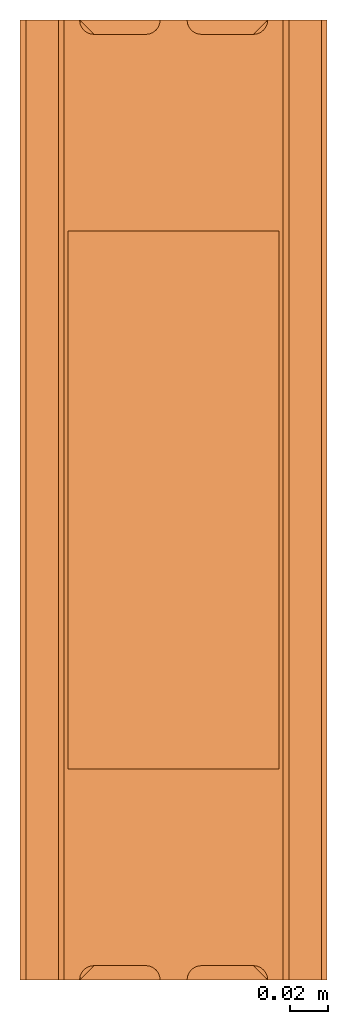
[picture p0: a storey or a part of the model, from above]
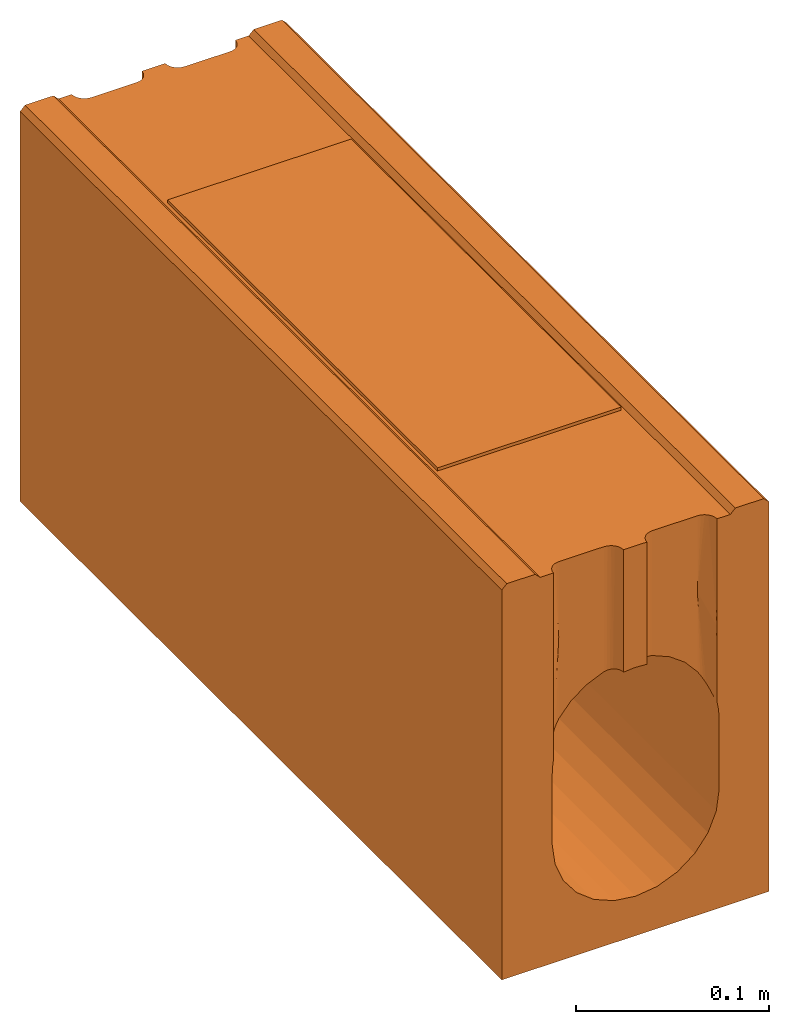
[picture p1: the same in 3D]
Properties of the parts of a building model (IFC2X3)

# File
Description: ViewDefinition [CoordinationView]
File name: 32103 - PD100 F 10.3 Rodding Access 500mm LG.ifc
Time: 2013-10-11T12:30:02
Written by: Autodesk Revit 2013
Made in: 20120221_2030(x64)

# IfcProject, Project Number
LongName: Project Name; Phase: Project Status

# IfcSite, Default
RefLatitude: 42, 21, 30, 344238; RefLongitude: -71, -3, -35, -194702; RefElevation: 0 mm

# IfcBuilding
Pset_BuildingCommon - NumberOfStoreys: 2
Other - Project Status: Project Status; Project Issue Date: Issue Date; Client Name: Owner; Project Address: Enter address here; Project Number: Project Number; Project Name: Project Name

# IfcBuildingStorey (2)
Constraints - Elevation Base: 0
Graphics - Symbol: M_Level Head - Circle: M_Level Head - Circle; Line Weight: 1; Line Pattern: Center; Symbol at End 2 Default: yes; Symbol at End 1 Default: no; Color: 0
Identity Data - Building Story: yes; Structural: no
Dimensions - Computation Height: 0 mm
Name | LongName = Name | Elevation (mm) = Constraints, Elevation (mm)
B.O. Footing | B.O. Footing | -4600
T.O. Footing | T.O. Footing | -4300

# IfcBuildingElementProxy: 32103 - PD100 F 10.3 Rodding Access 500mm LG, Civil-Drainage-Channel-ACO-RoadDrain 100:32103 - PD100 F 10.3 Rodding Access 500mm LG:32103 - PD100 F 10.3 Rodding Access 500mm LG:310733
In: B.O. Footing
Material: Acetal Resin, Black
Other - Revision: 1; CreatedBy: www.aco.co.uk
Green Building Properties - End Cap Recyclable: N/A; Access Cover/Frame Recycled Material Content: Between 40% - 90%; Grating Recycled Material Content: N/A; End Cap Recycled Material Content: N/A; Channel Recycled Material Content: 20% minimum; Grating Recyclable: N/A; Access Cover/Frame Recyclable: Fully recyclable; Channel Recyclable: Fully recyclable
Construction - 32900 - Sump Unit: no; Inlet Outlet end cap_350 high: no; Closing End Cap: no; Access unit: yes; Inlet Outlet end cap_450 high: no; Channel 160mm Wide: no; Grating 500mm: no
Dimensions - Straight Void Length: 500 mm; Volume: 13568465 mm3; Length: 500 mm; Custom Void Length: 0 mm; I/O End Cap Void: 3000 mm; Void Depth: -250 mm; Total Depth: 250 mm; Straight Void Start: 0 mm; Invert Depth.: 175 mm
Phasing - Phase Created: Phase 1
Constraints - Moves With Nearby Elements: no; Level: Level: T.O. Footing
Pset_BuildingElementProxyCommon - Reference: 32103 - PD100 F 10.3 Rodding Access 500mm LG
Identity Data - Product Page URL: http://www.aco.co.uk/product_detail.php?id=21; Address: ACO Business Park, Hitchin Road, Shefford, Bedfordshire, United Kingdom SG17 5TE; Assembly Description: Rain Water Drainage; Cost: 0; Type Comments: ACO RoadDrain 100 PD100F 10.3 Constant Depth Access Channel 500mm Long; Model: ACO RoadDrain 100 PD100F; Price: POA - contact ACO; Installation guidelines: http://www.aco.co.uk/download.php?id=256; URL: www.aco.co.uk; Manufacturer: ACO Technologies plc - ACO Water Management Division; Watermarked By: www.aco.co.uk; Watermark 1: This file is the property of ACO Technologies PLC; Telephone: +44 (0)1462 816666; e-mail Technical: technical@aco.co.uk; Assembly Code: D2040; OmniClass Title: Rainwater Removal; Product Code: 32103; Watermarked With: BIM Manager Premium Suite; OmniClass Number: 23.70.50.24; Watermark 2: This file is water marked and users are prohibited to reproduce, adapt, distribute this information; Product brochure: http://www.aco.co.uk/download.php?id=256; Fax: +44 (0)1462 815895; Maintenance guidelines: http://www.aco.co.uk/download.php?id=256; e-mail Sales: customersupport@aco.co.uk; Model Description: Monolithic Channel drainage system
Materials and Finishes - Access Cover/Frame Material: Ductile Iron; End Cap Colour: N/A; Access Cover/Frame Finish: Water Based Paint Coating; Access Cover/Frame Colour: Black; Channel Colour: Black; End Cap Material: N/A; Connection Pipe Colour: N/A; Channel Material: Vienite® Synthetic Resin Concrete; Grating Finish: N/A; Grating Colour: N/A; Connection Pipe Material: N/A; Grating Material: N/A
Data - Product Dimensions: 500mm x 160mm x 250mm (LxWxH); Product Standard: BE EN1433:2002, CE Marked, Kitemarked; ACO Hydraulic Design Software: http://www.acodesign.co.uk; Product Weight: 26.4 Kg; Load Class: A 15 - F 900; Hydraulic Performance: http://www.aco.co.uk/download.php?id=256; Connection Pipe O.D: N/A; Invert Depth: 225mm; Concrete Surround Volume - Load Class F 900 - Concrete Pavement: 0.22m³; Installation - Concrete Grade: Refer to brochure; Channel C.S.A: 0.012m²
General - TagNumber: 0.000000; SerialNumber: 0.000000

# IfcOpeningElement: Recess (2)
In: T.O. Footing
Constraints - Level: Level: T.O. Footing; Height Offset From Level: 0 mm; Room Bounding: yes; Related to Mass: no
Dimensions - Perimeter: 22200 mm; Thickness: 1550 mm; Volume: 47720000000 mm3; Area: 30800000 mm2
Structural - Structural: no; Enable Analytical Model: no
Phasing - Phase Created: Phase 1
Analytical Properties - Thermal Resistance (R): 1.79211; Roughness: 1; Heat Transfer Coefficient (U): 0.558; Thermal mass: 2039700; Absorptance: 0.1
Construction - Default Thickness: 1550 mm; Function: 0
Materials and Finishes - Structural Material: Grass
Graphics - Coarse Scale Fill Color: 0

# IfcSlab: Floor:Generic Floor - 400mm, Floor:Generic Floor - 400mm:136436
In: T.O. Footing
PredefinedType: FLOOR; Material: Grass 50 mm, Earth 1500 mm
Constraints - Level: Level: T.O. Footing; Height Offset From Level: 0 mm; Room Bounding: yes; Related to Mass: no
Dimensions - Perimeter: 22200 mm; Thickness: 1550 mm; Volume: 47720000000 mm3; Area: 30800000 mm2
Structural - Structural: no; Enable Analytical Model: no
Phasing - Phase Created: Phase 1
Pset_SlabCommon - Reference: Generic Floor - 400mm; IsExternal: no; LoadBearing: yes
Analytical Properties - Thermal Resistance (R): 1.79211; Roughness: 1; Heat Transfer Coefficient (U): 0.558; Thermal mass: 2039700; Absorptance: 0.1
Construction - Default Thickness: 1550 mm; Function: 0
Materials and Finishes - Structural Material: Grass
Graphics - Coarse Scale Fill Color: 0
